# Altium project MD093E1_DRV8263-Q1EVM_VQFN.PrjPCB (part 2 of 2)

## Sheet MD093E1_DRV8263-Q1EVM_VQFN.SchDoc
size 431 x 279 mm; Date: Not shown in title block; ApprovedBy: Not shown in title block; CheckedBy: Not shown in title block; Author: Not shown in title block; CompanyName: Not shown in title block; Engineer: Not shown in title block; Organization: Not shown in title block; Address1: Not shown in title block; Address2: Not shown in title block; Address3: Not shown in title block; Address4: Not shown in title block; DocumentNumber: 2; Revision: Use project parameter SCH_Rev; SheetNumber: 2; SheetTotal: 3; PageSetup: Record=PageOptions¦CenterHorizontal=True¦CenterVertical=True¦PrintScale=1.00¦XCorrection=1.00¦YCorrection=1.00¦PrintKind=0¦BorderSize=5000000¦LeftOffset=0¦BottomOffset=0¦Orientation=2¦PaperLength=1000¦PaperWidth=1000¦Scale=100¦PaperSource=15¦PrintQuality=600¦MediaType=1¦DitherType=10¦PaperKind=Letter¦PrintScaleMode=1

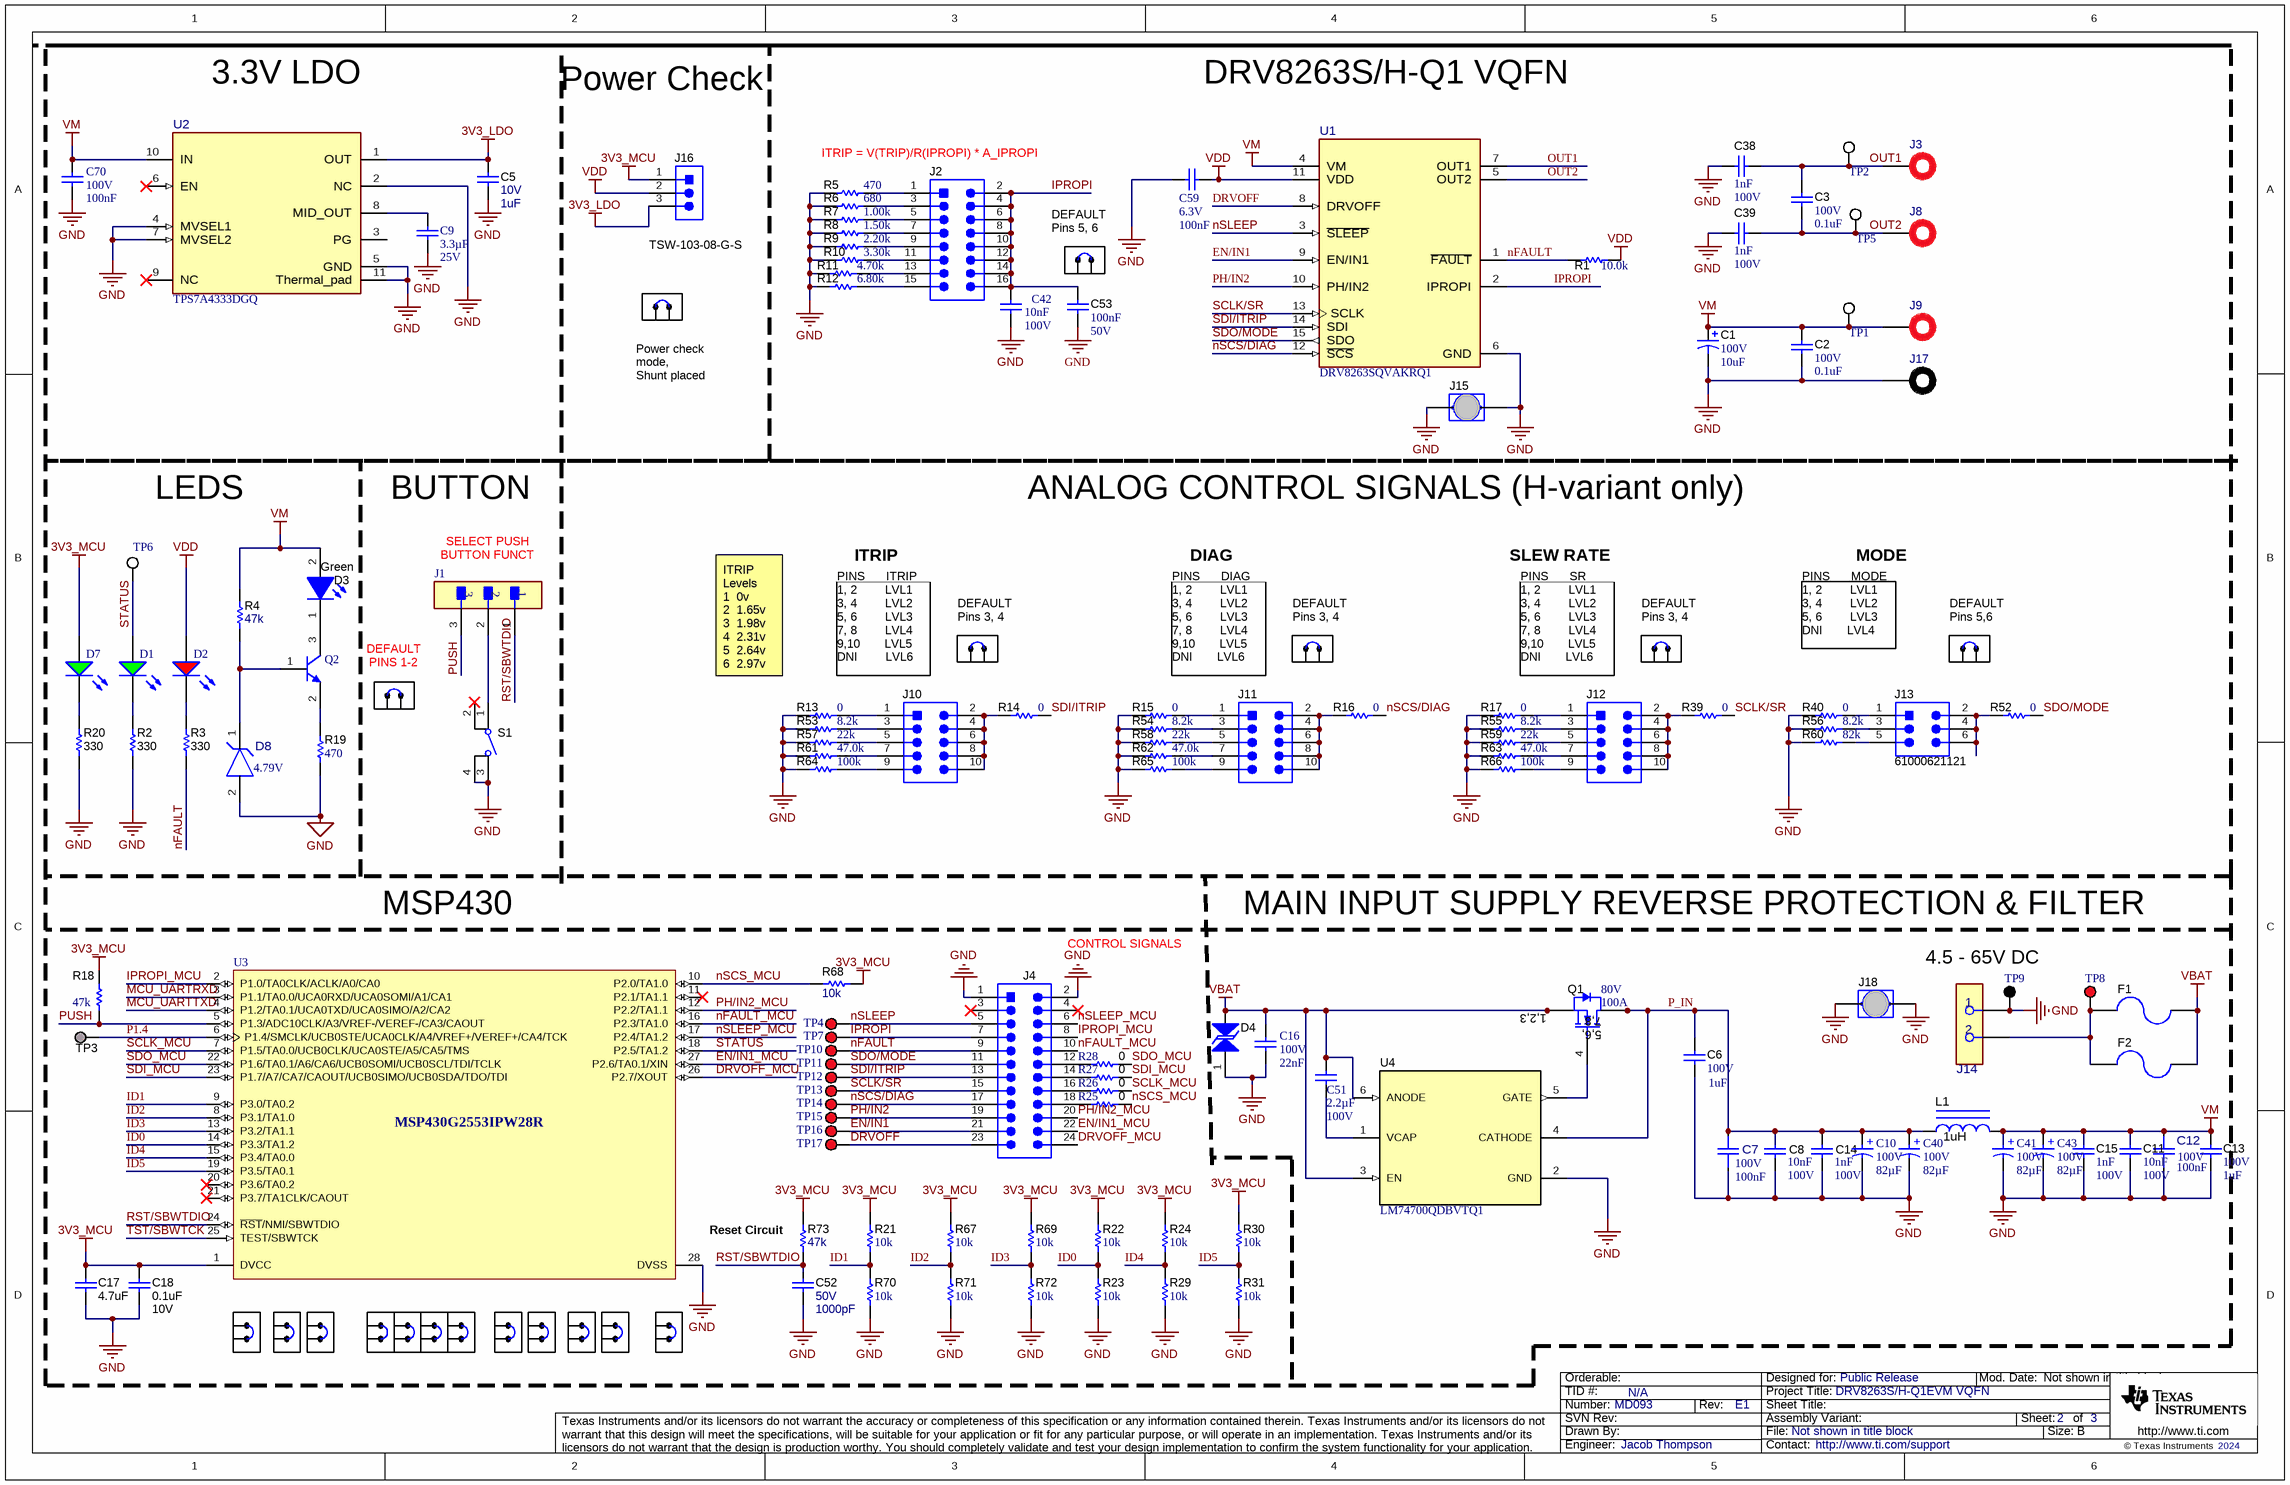
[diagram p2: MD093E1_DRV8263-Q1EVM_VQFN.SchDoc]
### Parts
C1  VDC_V: 100V  ValueDisplayed: 10uF  [SM_RADIAL_E]  (hidden comment: EEE-2AA100UP)
C2  VDC_V: 100V  ValueDisplayed: 0.1uF  [1206_180]  (hidden comment: C3216X7R2A104K160AA)
C3  VDC_V: 100V  ValueDisplayed: 0.1uF  [1206_180]  (hidden comment: C3216X7R2A104K160AA)
C5  VDC_V: 10V  ValueDisplayed: 1uF  [0402]  (hidden comment: 885012105012)
C6  VDC_V: 100V  ValueDisplayed: 1uF  [0805_HV]  (hidden comment: C2012X7S2A105K125AB)
C7  VDC_V: 100V  Cap_F: 100nF  [FP-885012206120_0603-MFG]  (hidden comment: 885012206120)
C8  Cap_F: 10nF  VDC_V: 100V  [0603]  (hidden comment: 885012206114)
C9  Cap_F: 3.3µF  Rated Voltage (DC): 25V  [WCAP-CSGP_1210_L3.2W2.5H1.6]  (hidden comment: 885012209026)
C10  Cap_F: 82µF  Rated Voltage (DC): 100V  [WCAP-ATUL_D10H20]  (hidden comment: 860040875004)
C11  Cap_F: 10nF  VDC_V: 100V  [0603]  (hidden comment: 885012206114)
C12  VDC_V: 100V  Cap_F: 100nF  [FP-885012206120_0603-MFG]  (hidden comment: 885012206120)
C13  VDC_V: 100V  ValueDisplayed: 1uF  [0805_HV]  (hidden comment: C2012X7S2A105K125AB)
C14  Cap_F: 1nF  VDC_V: 100V  [0603]  (hidden comment: 06031C102KAT2A)
C15  Cap_F: 1nF  VDC_V: 100V  [0603]  (hidden comment: 06031C102KAT2A)
C16  Cap_F: 22nF  Rated Voltage (DC): 100V  [WCAP-CSGP_0805_L2W1.25H0.8_Reflow]  (hidden comment: 885012207124)
C17  ValueDisplayed: 4.7uF  [0402_065L]  (hidden comment: Capacitor)
C18  ValueDisplayed: 0.1uF  VDC_V: 10V  [0603L]  (hidden comment: 885012206020)
C38  Cap_F: 1nF  VDC_V: 100V  [0603]  (hidden comment: CGA3E2X7R2A102K080AA)
C39  Cap_F: 1nF  VDC_V: 100V  [0603]  (hidden comment: CGA3E2X7R2A102K080AA)
C40  Cap_F: 82µF  Rated Voltage (DC): 100V  [WCAP-ATUL_D10H20]  (hidden comment: 860040875004)
C41  Cap_F: 82µF  Rated Voltage (DC): 100V  [WCAP-ATUL_D10H20]  (hidden comment: 860040875004)
C42  Cap_F: 10nF  Rated Voltage (DC): 100V  [WCAP-CSST_0805_L2W1.25H1.25]  (hidden comment: 885382207009)
C43  Cap_F: 82µF  Rated Voltage (DC): 100V  [WCAP-ATUL_D10H20]  (hidden comment: 860040875004)
C51  Cap_F: 2.2µF  Rated Voltage (DC): 100V  [WCAP-CSST_1210_L3.2W2.5H2.5]  (hidden comment: 885382209002)
C52  VDC_V: 50V  ValueDisplayed: 1000pF  [0402]  (hidden comment: GRM155R71H102KA01D)
C53  Cap_F: 100nF  VDC_V: 50V  [0603]  (hidden comment: CGA3E2X7R1H104K080AA)
C59  Cap_F: 100nF  Rated Voltage (DC): 6.3V  [WCAP-CSGP_0402_L1W0.5H0.5]  (hidden comment: 885012105001)
C70  Cap_F: 100nF  Rated Voltage (DC): 100V  [WCAP-CSGP_0805_L2W1.25H1.25]  (hidden comment: 885012207128)
D1  150080VS75000  [WL-SMCW_0805_150080xx75000]  (value not drawn)
D2  150080SS75000  [WL-SMCW_0805_150080xx75000]  (value not drawn)
D3  value Green  [WL-SMCW_GREEN]  (hidden comment: 150060VS75000)
D4  SMBJ33CA-13-F  [SMB-Bi]  (value not drawn)
D7  150080VS75000  [WL-SMCW_0805_150080xx75000]  (value not drawn)
D8  Vf_V: 4.79V  [FP-BZX84J-B4V7,115_SC90-MFG]  (hidden comment: BZX84J-B4V7,115)
F1  0463030.ER  [Fuse_0463]  (value not drawn)
F2  0463030.ER  [Fuse_0463]  (value not drawn)
J1  PR20203VBNN  [FP-PR20203VBNN-MFG]  (value not drawn)
J2  TSM-108-01-L-DV  [Samtec_TSM-108-01-x-DV]  (value not drawn)
J3  CT3151SP-2  [CTE_CT3151SP-2]  (value not drawn)
J4  67997-224HLF  [FCI_67997-224HLF]  (value not drawn)
J8  CT3151SP-2  [CTE_CT3151SP-2]  (value not drawn)
J9  CT3151SP-2  [CTE_CT3151SP-2]  (value not drawn)
J10  TSM-105-01-L-DV-P  [Samtec_TSM-105-01-x-DV]  (value not drawn)
J11  TSM-105-01-L-DV-P  [Samtec_TSM-105-01-x-DV]  (value not drawn)
J12  TSM-105-01-L-DV-P  [Samtec_TSM-105-01-x-DV]  (value not drawn)
J13  61000621121  [Wurth_61000621121]
J14  691256610002  [FP-691256610002_HDR2-MFG]  (value not drawn)
J15  D3082-05  [Harwin_D3082-05]  (value not drawn)
J16  TSW-103-08-G-S  [Samtec_TSW-103-08-x-S]
J17  CT3151SP-0  [CTE_CT3151SP-0]  (value not drawn)
J18  D3082-05  [Harwin_D3082-05]  (value not drawn)
L1  ValueDisplayed: 1uH  [WE-HCC_1210]  (hidden comment: 7443320100)
Q1  VdsMax_V: 80V  IdsMax_A: 100A  [DNK0008A]  (hidden comment: CSD19502Q5B)
Q2  BC846BLT1G  [ONSC-SOT-23-3-318-08_V]  (value not drawn)
R1  ValueDisplayed: 10.0k  [0603]  (hidden comment: RNCF0603TKY10K0)
R2  ValueDisplayed: 330  [0603L]  (hidden comment: CMP-0025785-4)
R3  ValueDisplayed: 330  [0603L]  (hidden comment: CMP-0025785-4)
R4  ValueDisplayed: 47k  [0402]  (hidden comment: CRCW040247K0JNED)
R5  ValueDisplayed: 470  [0603]  (hidden comment: RC0603FR-07470RL)
R6  ValueDisplayed: 680  [0603]  (hidden comment: RC0603FR-07680RL)
R7  ValueDisplayed: 1.00k  [0603]  (hidden comment: RC0603FR-071KL)
R8  ValueDisplayed: 1.50k  [0603]  (hidden comment: RC0603FR-071K5L)
R9  ValueDisplayed: 2.20k  [0603]  (hidden comment: RC0603FR-072K2L)
R10  ValueDisplayed: 3.30k  [0603]  (hidden comment: RC0603FR-073K3L)
R11  ValueDisplayed: 4.70k  [0603]  (hidden comment: RC0603FR-074K7L)
R12  ValueDisplayed: 6.80k  [0603]  (hidden comment: RC0603FR-076K8L)
R13  ValueDisplayed: 0  [0603]  (hidden comment: PMR03EZPJ000)
R14  ValueDisplayed: 0  [0603]  (hidden comment: PMR03EZPJ000)
R15  ValueDisplayed: 0  [0603]  (hidden comment: PMR03EZPJ000)
R16  ValueDisplayed: 0  [0603]  (hidden comment: PMR03EZPJ000)
R17  ValueDisplayed: 0  [0603]  (hidden comment: PMR03EZPJ000)
R18  ValueDisplayed: 47k  [0603]  (hidden comment: RC0603JR-0747KL)
R19  ValueDisplayed: 470  [0603]  (hidden comment: RC0603FR-07470RL)
R20  ValueDisplayed: 330  [0603L]  (hidden comment: CMP-0025785-4)
R21  ValueDisplayed: 10k  [0603]  (hidden comment: RC0603JR-0710KL)
R22  ValueDisplayed: 10k  [0603]  (hidden comment: RC0603JR-0710KL)
R23  ValueDisplayed: 10k  [0603]  (hidden comment: RC0603JR-0710KL)
R24  ValueDisplayed: 10k  [0603]  (hidden comment: RC0603JR-0710KL)
R25  value 0  [RESC1609X55X30NL10T20]  (hidden comment: CRCW06030000Z0EAHP)
R26  value 0  [RESC1609X55X30NL10T20]  (hidden comment: CRCW06030000Z0EAHP)
R27  value 0  [RESC1609X55X30NL10T20]  (hidden comment: CRCW06030000Z0EAHP)
R28  value 0  [RESC1609X55X30NL10T20]  (hidden comment: CRCW06030000Z0EAHP)
R29  ValueDisplayed: 10k  [0603]  (hidden comment: RC0603JR-0710KL)
R30  ValueDisplayed: 10k  [0603]  (hidden comment: RC0603JR-0710KL)
R31  ValueDisplayed: 10k  [0603]  (hidden comment: RC0603JR-0710KL)
R39  ValueDisplayed: 0  [0603]  (hidden comment: PMR03EZPJ000)
R40  ValueDisplayed: 0  [0603]  (hidden comment: PMR03EZPJ000)
R52  ValueDisplayed: 0  [0603]  (hidden comment: PMR03EZPJ000)
R53  ValueDisplayed: 8.2k  [0603]  (hidden comment: CRCW06038K20JNEA)
R54  ValueDisplayed: 8.2k  [0603]  (hidden comment: CRCW06038K20JNEA)
R55  ValueDisplayed: 8.2k  [0603]  (hidden comment: CRCW06038K20JNEA)
R56  ValueDisplayed: 8.2k  [0603]  (hidden comment: CRCW06038K20JNEA)
R57  ValueDisplayed: 22k  [0603]  (hidden comment: CRCW060322K0JNEA)
R58  ValueDisplayed: 22k  [0603]  (hidden comment: CRCW060322K0JNEA)
R59  ValueDisplayed: 22k  [0603]  (hidden comment: CRCW060322K0JNEA)
R60  ValueDisplayed: 82k  [0603]  (hidden comment: CRCW060382K0JNEA)
R61  ValueDisplayed: 47.0k  [0603]  (hidden comment: CRCW060347K0FKEA)
R62  ValueDisplayed: 47.0k  [0603]  (hidden comment: CRCW060347K0FKEA)
R63  ValueDisplayed: 47.0k  [0603]  (hidden comment: CRCW060347K0FKEA)
R64  ValueDisplayed: 100k  [0603]  (hidden comment: CRCW0603100KDHEAP)
R65  ValueDisplayed: 100k  [0603]  (hidden comment: CRCW0603100KDHEAP)
R66  ValueDisplayed: 100k  [0603]  (hidden comment: CRCW0603100KDHEAP)
R67  ValueDisplayed: 10k  [0603]  (hidden comment: RC0603JR-0710KL)
R68  ValueDisplayed: 10k  [0603]  (hidden comment: RC0603JR-0710KL)
R69  ValueDisplayed: 10k  [0603]  (hidden comment: RC0603JR-0710KL)
R70  ValueDisplayed: 10k  [0603]  (hidden comment: RC0603JR-0710KL)
R71  ValueDisplayed: 10k  [0603]  (hidden comment: RC0603JR-0710KL)
R72  ValueDisplayed: 10k  [0603]  (hidden comment: RC0603JR-0710KL)
R73  ValueDisplayed: 47k  [0402]  (hidden comment: CRCW040247K0JNED)
S1  FSM4JSMA  [SW_FSM4JSMA]  (value not drawn)
SH-J1  60900213421  [Wurth_60900213421]  (value not drawn)
SH-J2  60900213421  [Wurth_60900213421]  (value not drawn)
SH-J3  60900213421  [Wurth_60900213421]  (value not drawn)
SH-J4  60900213421  [Wurth_60900213421]  (value not drawn)
SH-J5  60900213421  [Wurth_60900213421]  (value not drawn)
SH-J6  60900213421  [Wurth_60900213421]  (value not drawn)
SH-J7  60900213421  [Wurth_60900213421]  (value not drawn)
SH-J8  60900213421  [Wurth_60900213421]  (value not drawn)
SH-J13  60900213421  [Wurth_60900213421]  (value not drawn)
SH-J14  60900213421  [Wurth_60900213421]  (value not drawn)
SH-J15  60900213421  [Wurth_60900213421]  (value not drawn)
SH-J16  60900213421  [Wurth_60900213421]  (value not drawn)
SH-J18  60900213421  [Wurth_60900213421]  (value not drawn)
SH-J19  60900213421  [Wurth_60900213421]  (value not drawn)
SH-J20  60900213421  [Wurth_60900213421]  (value not drawn)
SH-J21  60900213421  [Wurth_60900213421]  (value not drawn)
SH-J22  60900213421  [Wurth_60900213421]  (value not drawn)
SH-J23  60900213421  [Wurth_60900213421]  (value not drawn)
SH-J24  60900213421  [Wurth_60900213421]  (value not drawn)
TP1  5016  [Testpoint_Keystone_Compact]  (value not drawn)
TP2  5016  [Testpoint_Keystone_Compact]  (value not drawn)
TP3  TP_H0.45P0.75  [TP_H045P075]  (value not drawn)  (no BOM)
TP4  5010  [Keystone5010]  (value not drawn)
TP5  5016  [Testpoint_Keystone_Compact]  (value not drawn)
TP6  5015  [Testpoint_Keystone_Miniature]  (value not drawn)
TP7  5010  [Keystone5010]  (value not drawn)
TP8  5010  [Keystone5010]  (value not drawn)
TP9  5011  [Keystone5011]  (value not drawn)
TP10  5010  [Keystone5010]  (value not drawn)
TP11  5010  [Keystone5010]  (value not drawn)
TP12  5010  [Keystone5010]  (value not drawn)
TP13  5010  [Keystone5010]  (value not drawn)
TP14  5010  [Keystone5010]  (value not drawn)
TP15  5010  [Keystone5010]  (value not drawn)
TP16  5010  [Keystone5010]  (value not drawn)
TP17  5010  [Keystone5010]  (value not drawn)
U1  DRV8263SQVAKRQ1  [VAK0015A-MFG]
U2  TPS7A4333DGQ  [DGQ0010E-MFG]
U3  MSP430G2553IPW28R  [PW0028A_N]
U4  LM74700QDBVTQ1  [DBV0006A_N]

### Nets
3V3_LDO: C5.1 J16.3 U2.1(OUT)
3V3_MCU: C17.1 C18.1 D7.2(A) J16.1 R18.2 R21.1 R22.1 R24.1 R30.1 R67.1 R68.1 R69.1 R73.2 U3.1(DVCC)
GND: C1.2(-) C2.2 C5.2 C6.1 C7.1 C8.1 C9.2 C10.2(N) C11.1 C12.1 C13.1 C14.2 C15.2 C16.2 C17.2 C18.2 C38.1 C39.1 C40.2(N) C41.2(N) C42.1 C43.2(N) C52.2 C53.2 C59.2 C70.2 D4.1 D8.2(anode) J4.1 J4.2 J14.1 J15.1 J15.2 J17.1 J18.1 J18.2 R2.1 R5.1 R6.1 R7.1 R8.1 R9.1 R10.1 R11.1 R12.1 R13.2 R15.2 R17.2 R19.1 R20.1 R23.2 R29.2 R31.2 R40.2 R53.1 R54.1 R55.1 R56.1 R57.1 R58.1 R59.1 R60.2 R61.1 R62.1 R63.1 R64.1 R65.1 R66.1 R70.2 R71.2 R72.2 S1.3 S1.4 TP9.1 U1.6(GND) U2.2(NC) U2.4(MVSEL1) U2.5(GND) U2.7(MVSEL2) U2.11(Thermal_pad) U3.28(DVSS) U4.2(GND)
VBAT: C16.1 C51.2 D4.2 F1.1 F2.1 Q1.1(S) Q1.2(S) Q1.3(S) U4.3(EN) U4.6(ANODE)
VDD: C59.1 D2.2(A) J16.2 R1.2 U1.11(VDD)
VM: C1.1(+) C2.1 C11.2 C12.2 C13.2 C15.1 C41.1(P) C43.1(P) C70.1 D3.2(A) J9.1 L1.2 R4.2 TP1.1 U1.4(VM) U2.10(IN)
DRVOFF: J4.23 TP17.1 U1.8(DRVOFF)
DRVOFF_MCU: J4.24 U3.26(P2.7/XOUT)
EN/IN1: J4.21 TP16.1 U1.9(EN/IN1)
EN/IN1_MCU: J4.22 U3.27(P2.6/TA0.1/XIN)
ID0: R22.2 R23.1 U3.14(P3.3/TA1.2)
ID1: R21.2 R70.1 U3.9(P3.0/TA0.2)
ID2: R67.2 R71.1 U3.8(P3.1/TA1.0)
ID3: R69.2 R72.1 U3.13(P3.2/TA1.1)
ID4: R24.2 R29.1 U3.15(P3.4/TA0.0)
ID5: R30.2 R31.1 U3.19(P3.5/TA0.1)
IPROPI: C42.2 C53.1 J2.2 J2.4 J2.6 J2.8 J2.10 J2.12 J2.14 J2.16 J4.7 TP7.1 U1.2(IPROPI)
IPROPI_MCU: J4.8 U3.2(P1.0/TA0CLK/ACLK/A0/CA0)
MCU_UARTRXD: U3.3(P1.1/TA0.0/UCA0RXD/UCA0SOMI/A1/CA1)
MCU_UARTTXD: U3.4(P1.2/TA0.1/UCA0TXD/UCA0SIMO/A2/CA2)
nFAULT: J4.9 R1.1 R3.1 TP10.1 U1.1(~{FAULT})
nFAULT_MCU: J4.10 U3.16(P2.3/TA1.0)
nSCS/DIAG: J4.17 R16.1 TP14.1 U1.12(~{SCS})
nSCS_MCU: R25.2 R68.2 U3.10(P2.0/TA1.0)
nSLEEP: J4.5 TP4.1 U1.3(~{SLEEP})
nSLEEP_MCU: J4.6 U3.17(P2.4/TA1.2)
OUT1: C3.1 C38.2 J3.1 TP2.1 U1.7(OUT1)
OUT2: C3.2 C39.2 J8.1 TP5.1 U1.5(OUT2)
P1.4: TP3.1 U3.6(P1.4/SMCLK/UCB0STE/UCA0CLK/A4/VREF+/VEREF+/CA4/TCK)
P_IN: C6.2 C7.2 C8.2 C10.1(P) C14.1 C40.1(P) L1.1 Q1.5(D) Q1.6(D) Q1.7(D) Q1.8(D) Q1.9(D) U4.4(CATHODE)
PH/IN2: J4.19 TP15.1 U1.10(PH/IN2)
PH/IN2_MCU: J4.20 U3.12(P2.2/TA1.1)
PUSH: J1.3 R18.1 U3.5(P1.3/ADC10CLK/A3/VREF-/VEREF-/CA3/CAOUT)
RST/SBWTDIO: C52.1 J1.1 R73.1 U3.24(~{RST}/NMI/SBWTDIO)
SCLK/SR: J4.15 R39.1 TP13.1 U1.13(SCLK)
SCLK_MCU: R26.2 U3.7(P1.5/TA0.0/UCB0CLK/UCA0STE/A5/CA5/TMS)
SDI/ITRIP: J4.13 R14.1 TP12.1 U1.14(SDI)
SDI_MCU: R27.2 U3.23(P1.7/A7/CA7/CAOUT/UCB0SIMO/UCB0SDA/TDO/TDI)
SDO/MODE: J4.11 R52.1 TP11.1 U1.15(SDO)
SDO_MCU: R28.2 U3.22(P1.6/TA0.1/A6/CA6/UCB0SOMI/UCB0SCL/TDI/TCLK)
STATUS: D1.2(A) TP6.1 U3.18(P2.5/TA1.2)
TST/SBWTCK: U3.25(TEST/SBWTCK)
NetC9_1: C9.1 U2.8(MID_OUT)
NetC51_1: C51.1 U4.1(VCAP)
NetD1_1: D1.1(K) R2.2
NetD2_1: D2.1(K) R3.2
NetD3_1: D3.1(K) Q2.3(C)
NetD7_1: D7.1(K) R20.2
NetD8_1: D8.1(cathode) Q2.1(B) R4.1
NetF1_2: F1.2 F2.2 J14.2 TP8.1
NetJ1_2: J1.2 S1.1
NetJ2_1: J2.1 R5.2
NetJ2_3: J2.3 R6.2
NetJ2_5: J2.5 R7.2
NetJ2_7: J2.7 R8.2
NetJ2_9: J2.9 R9.2
NetJ2_11: J2.11 R10.2
NetJ2_13: J2.13 R11.2
NetJ2_15: J2.15 R12.2
NetJ4_12: J4.12 R28.1
NetJ4_14: J4.14 R27.1
NetJ4_16: J4.16 R26.1
NetJ4_18: J4.18 R25.1
NetJ10_1: J10.1 R13.1
NetJ10_2: J10.2 J10.4 J10.6 J10.8 J10.10 R14.2
NetJ10_3: J10.3 R53.2
NetJ10_5: J10.5 R57.2
NetJ10_7: J10.7 R61.2
NetJ10_9: J10.9 R64.2
NetJ11_1: J11.1 R15.1
NetJ11_2: J11.2 J11.4 J11.6 J11.8 J11.10 R16.2
NetJ11_3: J11.3 R54.2
NetJ11_5: J11.5 R58.2
NetJ11_7: J11.7 R62.2
NetJ11_9: J11.9 R65.2
NetJ12_1: J12.1 R17.1
NetJ12_2: J12.2 J12.4 J12.6 J12.8 J12.10 R39.2
NetJ12_3: J12.3 R55.2
NetJ12_5: J12.5 R59.2
NetJ12_7: J12.7 R63.2
NetJ12_9: J12.9 R66.2
NetJ13_1: J13.1 R40.1
NetJ13_2: J13.2 J13.4 J13.6 R52.2
NetJ13_3: J13.3 R56.2
NetJ13_5: J13.5 R60.1
NetQ1_4: Q1.4(G) U4.5(GATE)
NetQ2_2: Q2.2(E) R19.2

Not connected (* = marked no-connect by the designer): J4 3* 4*; S1 2*; U2 3(PG) 6(EN)* 9(NC)*; U3 11(P2.1/TA1.1)* 20(P3.6/TA0.2)* 21(P3.7/TA1CLK/CAOUT)*

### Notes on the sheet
- 3.3V LDO
- Power Check
- DRV8263S/H-Q1 VQFN
- ITRIP = V(TRIP)/R(IPROPI) * A_IPROPI
- (near SH-J6) DEFAULT
  Pins 5, 6
- (near SH-J20) Power check mode,
  Shunt placed
- LEDS
- BUTTON
- ANALOG CONTROL SIGNALS (H-variant only)
- SELECT PUSH
- (near J1) BUTTON FUNCT
- ITRIP
- DIAG
- SLEW RATE
- MODE
- PINS      ITRIP
- (near SH-J3) DEFAULT
  Pins 3, 4
- PINS      DIAG
- (near SH-J4) DEFAULT
  Pins 3, 4
- PINS      SR
- (near SH-J5) DEFAULT
  Pins 3, 4
- PINS      MODE
- (near SH-J2) DEFAULT
  Pins 5,6
- DEFAULT
- (near SH-J1) PINS 1-2
- ITRIP Levels
  1  0v
  2  1.65v
  3  1.98v
  4  2.31v
  5  2.64v
  6  2.97v
- 1, 2        LVL1
  3, 4        LVL2
  5, 6        LVL3
  7, 8        LVL4
  9,10       LVL5
  DNI        LVL6
- 1, 2        LVL1
  3, 4        LVL2
  5, 6        LVL3
  7, 8        LVL4
  9,10       LVL5
  DNI       LVL6
- 1, 2        LVL1
  3, 4        LVL2
  5, 6        LVL3
  DNI       LVL4
- MSP430
- MAIN INPUT SUPPLY REVERSE PROTECTION & FILTER
- CONTROL SIGNALS
- 4.5 - 65V DC
- (near R73) Reset Circuit

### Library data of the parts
C1 = CMP-0011164-2: CAP, AL, 10 uF, 100 V, +/- 20%, AEC-Q200 Grade 3, SMD; Manufacturer: Panasonic; TaMin_C: -40°C; Polarized: Y; SizeAreaWB_mm2: 118.45; Value1: Unknown; U/M: EA; Value: 10uF; TaMax_C: 85°C; SizeZ_mm: 6.2; SizeX_mm: 9.5; SizeY_mm: 8.3; Cap_Case: 8.0x6.0mm; SizeArea_mm2: 78.85; CompType: Capacitor; Cap_F: 10µF; IRMS_A: 50mA; AEC Grade: 3; AEC Category: Q200
C2 C3 = CMP-0008709-2: CAP, CERM, 0.1 uF, 100 V, +/- 10%, X7R, 1206; Manufacturer: TDK; TaMin_C: -55°C; ESR_ohm: 30.343m; Polarized: N; SizeAreaWB_mm2: 10.92; Value1: 0.030343 ohm; U/M: EA; Value: 0.1uF; TaMax_C: 125°C; SizeZ_mm: 1.8; SizeX_mm: 3.2; SizeY_mm: 1.6; SizeArea_mm2: 5.12; Cap_F: 100nF; IRMS_A: 1.338A; AEC Category: Q200
C5 = CMP-0064924-2: CAP, CERM, 1 uF, 10 V,+/- 20%, X5R, 0402; Manufacturer: Wurth Elektronik; TaMin_C: -55°C; Polarized: N; SizeAreaWB_mm2: 3; Value1: Unknown; U/M: EA; Value: 1uF; TaMax_C: 85°C; SizeZ_mm: 0.6; SizeX_mm: 1; SizeY_mm: 0.5; Cap_F: 1µF; AEC Category: Q200
C6 C13 = CMP-0007891-2: CAP, CERM, 1 uF, 100 V, +/- 10%, X7S, 0805; Manufacturer: TDK; TaMin_C: -55°C; ESR_ohm: 8.255m; Polarized: N; SizeAreaWB_mm2: 6.75; Value1: 0.008255 ohm; U/M: EA; Value: 1uF; TaMax_C: 125°C; SizeZ_mm: 1.45; SizeX_mm: 2; SizeY_mm: 1.25; Cap_Case: 0805; SizeArea_mm2: 2.5; Cap_F: 1µF; IRMS_A: 2.27442A; AEC Category: Q200
C7 C12 = CMP-0097294-1: 0.1 µF ±10% 100V Ceramic Capacitor X7R 0603 (1608 Metric); Manufacturer: Wurth Electronics; TempCo: 15%; SizeZ_mm: 0.87mm; Value: 100nF; AEC Qualified: No
C8 C11 = CMP-0079993-1: CAP, CERM, 0.01 µF, 100 V,+/- 10%, X7R, 0603; Manufacturer: Wurth Elektronik; TaMin_C: -55°C; Polarized: N; SizeAreaWB_mm2: 4.68; U/M: EA; Value: 0.01uF; TaMax_C: 105°C; SizeZ_mm: 1; SizeX_mm: 1.6; SizeY_mm: 0.8; SizeArea_mm2: 1.28; AEC Category: Q200; ValueDisplayed: 0.01µF
C9 = CMP-0105009-1: WCAP-CSGP Multilayer Ceramic Chip Capacitor, General Purpose, size 1210, X7R, 3.3µF, 25VDC; Manufacturer: Wurth Elektronik; Capacitance Tolerance: +/-10%; Dissipation Factor: 3.5%; Insulation Resistance: 0.2GOhm; Technical Reference: X7R1210335K025DFCT10000
C10 C40 C41 C43 = CMP-0102582-1: WCAP-ATUL Aluminum Electrolytic Capacitor, Radial, THT, D10 x H20mm, 82µF, 100V; Manufacturer: Wurth Elektronik; Capacitance Tolerance: 20%; Dissipation Factor: 9%; Endurance: 7000h; Leakage Current: 82uA; Ripple Current: 600mA; Technical Reference: ATDF200820M100DSPAAG000
C14 C15 = CMP-0006724-5: CAP, CERM, 1000 pF, 100 V, +/- 10%, X7R, 0603; Manufacturer: AVX; TaMin_C: -55°C; ESR_ohm: 2.76d; Polarized: N; SizeAreaWB_mm2: 4.68; Value1: 0.276 ohm; U/M: EA; Value: 1000pF; TaMax_C: 125°C; SizeZ_mm: 1; SizeX_mm: 1.6; SizeY_mm: 0.8; SizeArea_mm2: 1.28; AEC Category: Q200
C16 = CMP-0115610-1: WCAP-CSGP Multilayer Ceramic Chip Capacitor, General Purpose, size 0805, X7R, 22nF, 100VDC; Manufacturer: Wurth Elektronik; Capacitance Tolerance: +/-10%; Dissipation Factor: 2.5%; Insulation Resistance: 4.5GOhm; Technical Reference: X7R0805223K100DFCT10000
C17 = CMP-0006268-2: CAP, CERM, 4.7 uF, 10 V, +/- 10%, X5R, 0402; PartNumber: C1005X5R1A475K050BC; Manufacturer: TDK; Polarized: N; Value: 4.7uF; U/M: EA; Cap_F: 4.7µF; ESR_ohm: 3.417m; Value1: 0.003417 ohm; VDC_V: 10V; IRMS_A: 2.7063A; TaMin_C: -55°C; TaMax_C: 85°C; Cap_Case: 0402_065; AEC Category: Q200; SizeArea_mm2: 0.5; SizeAreaWB_mm2: 3; SizeX_mm: 1; SizeZ_mm: 0.65
C18 = CMP-0064931-4: CAP, CERM, 0.1 uF, 10 V,+/- 10%, X7R, 0603; Manufacturer: Wurth Elektronik; Polarized: N; CompType: Capacitor; Value: 0.1uF; U/M: EA; Cap_F: 100nF; Value1: Unknown; TaMin_C: -55°C; TaMax_C: 125°C; Cap_Case: 0603; AEC Category: Q200; SizeArea_mm2: 1.28; SizeAreaWB_mm2: 4.68; SizeX_mm: 1.6; SizeY_mm: 0.8; SizeZ_mm: 1
C38 C39 = CMP-0007081-4: CAP, CERM, 1000 pF, 100 V, +/- 10%, X7R, AEC-Q200 Grade 1, 0603; Manufacturer: TDK; TaMin_C: -55°C; ESR_ohm: 1.97137; Polarized: N; SizeAreaWB_mm2: 4.68; Value1: 1.97137 ohm; U/M: EA; Value: 1000pF; TaMax_C: 125°C; SizeZ_mm: 1; SizeX_mm: 1.6; SizeY_mm: 0.8; SizeArea_mm2: 1.28; AEC Qualified: Y; IRMS_A: 305.705mA; AEC Category: Q200
C42 = CMP-0105213-1: WCAP-CSST Multilayer Ceramic Chip Capacitor, Soft Termination, size 0805, X7R Class II, 10nF, 100VDC; Manufacturer: Wurth Elektronik; Capacitance Tolerance: +/-10%; Dissipation Factor: 2.5%; Insulation Resistance: 10GOhm; Technical Reference: X7R0805103K100DFCT1S000
C51 = CMP-0119921-1: WCAP-CSST Multilayer Ceramic Chip Capacitor, Soft Termination, size 1210, X7R Class II, 2.2µF, 100VDC; Manufacturer: Wurth Elektronik; Capacitance Tolerance: +/-10%; Dissipation Factor: 5%; Insulation Resistance: 0.05GOhm; Technical Reference: X7R1210225K100DFCT1S000
C52 = CMP-0006673-2: CAP, CERM, 1000 pF, 50 V, +/- 10%, X7R, 0402; Manufacturer: MuRata; TaMin_C: -55°C; Polarized: N; SizeAreaWB_mm2: 3; Value1: Unknown; U/M: EA; Value: 1000pF; TaMax_C: 125°C; SizeZ_mm: 0.6; SizeX_mm: 1; SizeY_mm: 0.5; Cap_F: 1nF; AEC Category: Q200
C53 = CMP-0007078-4: CAP, CERM, 0.1 uF, 50 V, +/- 10%, X7R, AEC-Q200 Grade 1, 0603; Manufacturer: TDK; TaMin_C: -55°C; ESR_ohm: 29.6m; Polarized: N; SizeAreaWB_mm2: 4.68; Value1: 0.0296 ohm; U/M: EA; Value: 0.1uF; TaMax_C: 125°C; SizeZ_mm: 1; SizeX_mm: 1.6; SizeY_mm: 0.8; SizeArea_mm2: 1.28; AEC Qualified: Y; IRMS_A: 971.99mA; AEC Category: Q200
C59 = CMP-0115207-1: WCAP-CSGP Multilayer Ceramic Chip Capacitor, General Purpose, size 0402, X5R, 100nF, 6.3VDC; Manufacturer: Wurth Elektronik; Capacitance Tolerance: +/-20%; Dissipation Factor: 10%; Insulation Resistance: 1GOhm; Technical Reference: X5R0402104M6R3DFCT10000
C70 = CMP-0108445-1: WCAP-CSGP Multilayer Ceramic Chip Capacitor, General Purpose, size 0805, X7R, 100nF, 100VDC; Manufacturer: Wurth Elektronik; Capacitance Tolerance: +/-10%; Dissipation Factor: 2.5%; Insulation Resistance: 1GOhm; Technical Reference: X7R0805104K100DFCT10000
D1 D7 = CMP-1426-00009-5: SMD mono-color Chip LED, WL-SMCW, Bright Green; NexarPartId: 29717783; Manufacturer: Wurth Elektronik; Dominant Wavelength: 570nm; Lens Style: Clear, Rectangular; Test Current: 20mA; Max Junction Temperature (Tj): 95°C; Max Reverse Voltage (DC): 5V; Forward Voltage: 2V; Forward Current: 100mA; Viewing Angle: 140°; Power Dissipation: 72mW; Peak Wavelength: 572nm; Luminous Intensity: 40mcd
D2 = CMP-1426-00010-3: SMD mono-color Chip LED, WL-SMCW, Super Red; NexarPartId: 29717782; Manufacturer: Wurth Elektronik; Peak Wavelength: 645nm; Luminous Intensity: 60mcd; Max Junction Temperature (Tj): 95°C; Wavelength: 630nm; Forward Current: 100mA; Max Reverse Voltage (DC): 5V; Lens Style: Clear, Rectangular; Test Current: 20mA; Power Dissipation: 72mW; Viewing Angle: 140°; Forward Voltage: 1.9V
D3 = CMP-0002894-2: LED, Green, SMD; Manufacturer: Wurth Elektronik; Type: AlInGaP; Value2: 2V; Io_A: 20mA; Value1: W
D4 = CMP-0005564-3: Diode, TVS, Bi, 33 V, SMB; Manufacturer: Diodes Inc.; Value: 33V; SizeX_mm: 5.6; Ppk: 600W; SizeAreaWB_mm2: 44.156; SizeZ_mm: 2.6; SizeArea_mm2: 21.336; SizeY_mm: 3.81; AEC Category: Q101
D8 = CMP-0097377-1: Diode Zener Single 4.7V 2% 550mW Automotive 2-Pin SOD-323F T/R; Manufacturer: Nexperia; TaMin_C: -55°C; Vr_V: 2V; SizeZ_mm: 0.8mm; Max Reverse Leakage Current: 3uA; TJmax_C: 150°C; Zener Impedance: 80Ω; AEC Grade: Grade 0; Forward Current: 250mA; TaMax_C: +150°C; AEC Qualified: Yes
F1 F2 = CMP-0077200-3: Fuse, 30 A, 250 VAC, 100 VDC, SMD; Manufacturer: Littelfuse; VAC_V: 250V; SizeAreaWB_mm2: 61.952; Rtyp_Ohm: 1.93m; SizeArea_mm2: 31.512; MeltingTyp: 916; Irating_A: 30A; SizeZ_mm: 3.12; VDC_V: 100V; SizeX_mm: 10.1; Interrupt_AC: 100A; Interrupt_DC: 50A; Fuse Speed: Fast; Fuse Technology: Board Mount; TaMax_C: 125°C; TaMin_C: -55°C
J1 = CMP-77940-000002-1: CONN HEADER VERT 3POS 2.54MM; Manufacturer: Metz Connect; Conn Orientation: Straight; Current Rating: 3A; Number Of Contacts: 3; Conn Gender: Male
J2 = CMP-0075595-1: Header, 2.54mm, 8x2, Gold, SMT; Manufacturer: Samtec; Pitch_mm: 2.54; Gender: Male; Cert_CSA: Y; Current_A: 4.9A; Voltage_V: 475V; CT: False; Shrouded: N; Row_Count: 2; CNHeader: True
J3 J8 J9 = CMP-0055418-2: Banana Jack Insul Nylon Red, R/A, TH; Manufacturer: Cal Test Electronics; CNHeader: FALSE; Current_A: 25A; Gender: Female; Voltage_V: 1kV; Row_Count: 1; ContactFinish: Nickel; CT: TRUE; Cert_UL: Y
J4 = CMP-0085938-1: Header, 2.54mm, 12x2, Gold, TH; Manufacturer: FCI; Current_A: 5A; Shrouded: N; Gender: Male; Voltage_V: 1.5kV; Row_Count: 2; Pitch_mm: 2.54; Cert_UL: Y
J10-J12 = CMP-0055598-2: Header, 2.54mm, 5x2, Gold, SMT; Manufacturer: Samtec; Current_A: 5.4A; Green_Lifecycle: Active; Shrouded: N; Gender: Male; Cert_CSA: Y; Green_REACh: Passed; Voltage_V: 475V; Row_Count: 2; RowSpacing_mm: 2.54
J13 = CMP-0079534-2: Header, 2.54mm, 3x2, Gold, SMT; Manufacturer: Wurth Elektronik; Pitch_mm: 2.54; Gender: Male; Cert_UL: Y; Current_A: 3A; Voltage_V: 250V; Shrouded: N; Row_Count: 2
J14 = CMP-0086764-1: Manufacturer: Wurth; Current_A: 57A; Voltage_V: 750V; ContactFinish: Zinc; Row_Count: 1
J15 J18 = CMP-0075110-1: 1mm Uninsulated Shorting Plug, 10.16mm spacing, TH; Manufacturer: Harwin; CNHeader: False; Green_Lifecycle: Active; Green_REACh: Passed; CompType: Jumper Wire
J16 = CMP-0079327-1: Header, 2.54mm, 3x1, Gold, TH; Manufacturer: Samtec; Cert_UL: Y; Row_Count: 1; Pitch_mm: 2.54; Gender: Male; Shrouded: N
J17 = CMP-0055417-2: Banana Jack Insul Nylon Black, R/A, TH; Manufacturer: Cal Test Electronics; CNHeader: FALSE; Current_A: 25A; Gender: Female; Voltage_V: 1kV; Row_Count: 1; ContactFinish: Nickel; CT: TRUE; Cert_UL: Y
L1 = CMP-0063986-1: Inductor, Shielded Drum Core, Ferrite, 1 uH, 24 A, 0.0012 ohm, SMD; Manufacturer: Wurth Elektronik; Isat: 32A @ 30% inductance drop; Irms: 24A @ 50C rise; Green_Lifecycle: Active; SizeAreaWB_mm2: 188.94; DCR_ohm: 1.2m; Green_REACh: Passed; Value: 1uH; Imax_A: 24A; SizeZ_mm: 10; SizeX_mm: 12.1; SizeY_mm: 11.4; SizeArea_mm2: 137.94; Ind_H: 1µH; AEC Category: Q200
Q1 = CMP-0000915-2: MOSFET, N-CH, 80 V, 100 A, DNK0008A (VSON-CLIP-8); Alternate Manufacturer: None; Manufacturer: Texas Instruments; SizeZ_mm: 1; ChType: N; Value2: 48 nC; SizeX_mm: 6; SizeY_mm: 5; Vgs_V: 20V; Value: 80V; SizeArea_mm2: 30; AEC Category: Q101; SizeAreaWB_mm2: 56; U/M: EA; QgTyp_nC: 48
Q2 = CMP-1048-00779-1: General Purpose Transistor, NPN Silicon, 3-Pin SOT-23, Pb-Free, Tape and Reel; Manufacturer: On Semiconductor; fT Min (MHz): 100; IC Continuous (A): 0.1
R1 = CMP-0023626-3: RES, 10.0 k, 0.01%, 0.063 W, 0603; Manufacturer: Stackpole Electronics Inc; Power_W: 63mW; TempCo: 5 ppm/C; Value_Code: 10k0; U/M: EA; Value: 10.0k; Res_ohm: 10k; SizeX_mm: 1.6; SizeY_mm: 0.8; SizeZ_mm: 1; Value2: 0.063W; SizeArea_mm2: 1.28; VDC_V: 50V; AEC Category: Q200
R2 R3 R20 = CMP-0025785-4: RES, 330, 5%, 0.1 W, AEC-Q200 Grade 0, 0603; PartNumber: CRCW0603330RJNEA; Manufacturer: Vishay-Dale; CompType: Resistor; Value: 330; Value_Code: 330R; Power_W: 100mW; Value2: 0.1W; VDC_V: 75V; TempCo: 200 ppm/C; EIA_Code: E24; AEC Category: Q200; AEC Qualified: Y; AEC Grade: 0; SizeX_mm: 1.6; SizeY_mm: 0.8; SizeZ_mm: 1; SizeArea_mm2: 1.28
R4 R73 = CMP-0026935-3: RES, 47 k, 5%, 0.063 W, AEC-Q200 Grade 0, 0402; Manufacturer: Vishay-Dale; Power_W: 63mW; TempCo: 200 ppm/C; Value_Code: 47k0; Value: 47k; EIA_Code: E24; SizeX_mm: 1; SizeY_mm: 0.5; SizeZ_mm: 0.6; Value2: 0.063W; AEC Qualified: Y; VDC_V: 50V; AEC Category: Q200; AEC Grade: 0
R5 R19 = CMP-0023129-5: RES, 470, 1%, 0.1 W, 0603; Manufacturer: Yageo; Power_W: 100mW; TempCo: 100 ppm/C; Value_Code: 470R; Value: 470; SizeX_mm: 1.6; SizeY_mm: 0.8; SizeZ_mm: 1; Value2: 0.1W; SizeArea_mm2: 1.28; AEC Qualified: N; VDC_V: 75V; AEC Category: Q200; SizeAreaWB_mm2: 4.68
R6 = CMP-0023235-5: RES, 680, 1%, 0.1 W, 0603; Manufacturer: Yageo; Power_W: 100mW; TempCo: 100 ppm/C; Value_Code: 680R; Value: 680; SizeX_mm: 1.6; SizeY_mm: 0.8; SizeZ_mm: 1; Value2: 0.1W; SizeArea_mm2: 1.28; AEC Qualified: N; VDC_V: 75V; AEC Category: Q200; SizeAreaWB_mm2: 4.68
R7 = CMP-0022895-5: RES, 1.00 k, 1%, 0.1 W, 0603; Manufacturer: Yageo; Power_W: 100mW; TempCo: 100 ppm/C; Value_Code: 1k00; Value: 1.00k; EIA_Code: E96; Res_ohm: 1k; SizeX_mm: 1.6; SizeY_mm: 0.8; SizeZ_mm: 1; Value2: 0.1W; SizeArea_mm2: 1.28; AEC Qualified: N; VDC_V: 75V; AEC Category: Q200; SizeAreaWB_mm2: 4.68
R8 = CMP-0022883-5: RES, 1.50 k, 1%, 0.1 W, 0603; Manufacturer: Yageo; Power_W: 100mW; TempCo: 100 ppm/C; Value_Code: 1k50; Value: 1.50k; EIA_Code: E96; Res_ohm: 1.5k; SizeX_mm: 1.6; SizeY_mm: 0.8; SizeZ_mm: 1; Value2: 0.1W; SizeArea_mm2: 1.28; AEC Qualified: N; VDC_V: 75V; AEC Category: Q200; SizeAreaWB_mm2: 4.68
R9 = CMP-0022986-5: RES, 2.20 k, 1%, 0.1 W, 0603; Manufacturer: Yageo; Power_W: 100mW; TempCo: 100 ppm/C; Value_Code: 2k20; Value: 2.20k; Res_ohm: 2.2k; SizeX_mm: 1.6; SizeY_mm: 0.8; SizeZ_mm: 1; Value2: 0.1W; SizeArea_mm2: 1.28; AEC Qualified: N; VDC_V: 75V; AEC Category: Q200; SizeAreaWB_mm2: 4.68
R10 = CMP-0023081-5: RES, 3.30 k, 1%, 0.1 W, 0603; Manufacturer: Yageo; Power_W: 100mW; TempCo: 100 ppm/C; Value_Code: 3k30; Value: 3.30k; Res_ohm: 3.3k; SizeX_mm: 1.6; SizeY_mm: 0.8; SizeZ_mm: 1; Value2: 0.1W; SizeArea_mm2: 1.28; AEC Qualified: N; VDC_V: 75V; AEC Category: Q200; SizeAreaWB_mm2: 4.68
R11 = CMP-0023153-5: RES, 4.70 k, 1%, 0.1 W, 0603; Manufacturer: Yageo; Power_W: 100mW; TempCo: 100 ppm/C; Value_Code: 4k70; Value: 4.70k; Res_ohm: 4.7k; SizeX_mm: 1.6; SizeY_mm: 0.8; SizeZ_mm: 1; Value2: 0.1W; SizeArea_mm2: 1.28; AEC Qualified: N; VDC_V: 75V; AEC Category: Q200; SizeAreaWB_mm2: 4.68
R12 = CMP-0023253-5: RES, 6.80 k, 1%, 0.1 W, 0603; Manufacturer: Yageo; Power_W: 100mW; TempCo: 100 ppm/C; Value_Code: 6k80; Value: 6.80k; Res_ohm: 6.8k; SizeX_mm: 1.6; SizeY_mm: 0.8; SizeZ_mm: 1; Value2: 0.1W; SizeArea_mm2: 1.28; AEC Qualified: N; VDC_V: 75V; AEC Category: Q200; SizeAreaWB_mm2: 4.68
R13-R17 R39 R40 R52 = CMP-0086358-1: RES, 0, 0%, 0.25 W, AEC-Q200 Grade 0, 0603; Manufacturer: Rohm; Power_W: 250mW; SizeZ_mm: 1; SizeArea_mm2: 1.28; Value2: 0.25W; SizeAreaWB_mm2: 4.68; Value_Code: 0000; Value: 0; AEC Qualified: Y; AEC Category: Q200; SizeX_mm: 1.6; SizeY_mm: 0.8
R18 = CMP-0025925-5: RES, 47 k, 5%, 0.1 W, 0603; Manufacturer: Yageo; Power_W: 100mW; TempCo: 100 ppm/C; Value_Code: 47k0; Value: 47k; EIA_Code: E24; SizeX_mm: 1.6; SizeY_mm: 0.8; SizeZ_mm: 1; Value2: 0.1W; SizeArea_mm2: 1.28; AEC Qualified: N; VDC_V: 75V; AEC Category: Q200; SizeAreaWB_mm2: 4.68
R21-R24 R29-R31 R67 R69-R72 = CMP-0025886-5: RES, 10 k, 5%, 0.1 W, 0603; Manufacturer: Yageo; Power_W: 100mW; TempCo: 100 ppm/C; Value_Code: 10k0; Value: 10k; EIA_Code: E24; SizeX_mm: 1.6; SizeY_mm: 0.8; SizeZ_mm: 1; Value2: 0.1W; SizeArea_mm2: 1.28; AEC Qualified: N; VDC_V: 75V; AEC Category: Q200; SizeAreaWB_mm2: 4.68
R25-R28 = CMP-2000-03817-1: Manufacturer: Vishay Dale
R53-R56 = CMP-0025862-4: RES, 8.2 k, 5%, 0.1 W, AEC-Q200 Grade 0, 0603; Manufacturer: Vishay-Dale; Power_W: 100mW; TempCo: 200 ppm/C; Value_Code: 8k20; Value: 8.2k; EIA_Code: E24; SizeX_mm: 1.6; SizeY_mm: 0.8; SizeZ_mm: 1; Value2: 0.1W; SizeArea_mm2: 1.28; AEC Qualified: Y; VDC_V: 75V; AEC Category: Q200; AEC Grade: 0
R57-R59 = CMP-0025757-4: RES, 22 k, 5%, 0.1 W, AEC-Q200 Grade 0, 0603; Manufacturer: Vishay-Dale; Power_W: 100mW; TempCo: 200 ppm/C; Value_Code: 22k0; Value: 22k; EIA_Code: E24; SizeX_mm: 1.6; SizeY_mm: 0.8; SizeZ_mm: 1; Value2: 0.1W; SizeArea_mm2: 1.28; AEC Qualified: Y; VDC_V: 75V; AEC Category: Q200; AEC Grade: 0
R60 = CMP-0025860-4: RES, 82 k, 5%, 0.1 W, AEC-Q200 Grade 0, 0603; Manufacturer: Vishay-Dale; Power_W: 100mW; TempCo: 200 ppm/C; Value_Code: 82k0; Value: 82k; EIA_Code: E24; SizeX_mm: 1.6; SizeY_mm: 0.8; SizeZ_mm: 1; Value2: 0.1W; SizeArea_mm2: 1.28; AEC Qualified: Y; VDC_V: 75V; AEC Category: Q200; AEC Grade: 0
R61-R63 = CMP-0022438-4: RES, 47.0 k, 1%, 0.1 W, AEC-Q200 Grade 0, 0603; Manufacturer: Vishay-Dale; Power_W: 100mW; TempCo: 100 ppm/C; Value_Code: 47k0; Value: 47.0k; Res_ohm: 47k; SizeX_mm: 1.6; SizeY_mm: 0.8; SizeZ_mm: 1; Value2: 0.1W; SizeArea_mm2: 1.28; AEC Qualified: Y; VDC_V: 75V; AEC Grade: 0; AEC Category: Q200
R64-R66 = CMP-0086261-1: RES, 100 k, 0.5%, 0.1 W, AEC-Q200 Grade 0, 0603; Manufacturer: Vishay-Dale; EIA_Code: E192; SizeZ_mm: 1; Power_W: 100mW; Value2: 0.1W; Value: 100k; SizeAreaWB_mm2: 4.68; AEC Qualified: Y; TempCo: 50 ppm/C; SizeArea_mm2: 1.28; AEC Category: Q200; SizeX_mm: 1.6; SizeY_mm: 0.8; AEC Grade: 0
R68 = CMP-0025886-3: RES, 10 k, 5%, 0.1 W, 0603; Manufacturer: Yageo America; Power_W: 100mW; TempCo: 100 ppm/C; Value_Code: 10k0; U/M: EA; Value: 10k; EIA_Code: E24; SizeX_mm: 1.6; SizeY_mm: 0.8; SizeZ_mm: 1; Value2: 0.1W; SizeArea_mm2: 1.28; VDC_V: 50V; AEC Category: Q200
S1 = CMP-0002134-3: Switch, Tactile, SPST-NO, 0.05A, 12V, SMT; Manufacturer: TE Connectivity; CurrentRating_mA: 50A; PositionCount: 1; SwitchFunction: Off-Mom
SH-J1-SH-J8 SH-J13-SH-J16 SH-J18-SH-J24 = CMP-0003761-2: Shunt, 2.54mm, Gold, Black; Manufacturer: Wurth Elektronik
TP1 TP2 TP5 = CMP-0055153-2: Test Point, Compact, SMT; Manufacturer: Keystone Electronics; Green_Lifecycle: Active; Green_REACh: Passed; CNHeader: FALSE; CT: TRUE
TP3 = CMP-0003719-1: Testpoint; Manufacturer: Texas Instruments; CompType: Pad
TP4 TP7 TP8 TP10-TP17 = CMP-0055147-2: Test Point, Multipurpose, Red, TH; Manufacturer: Keystone Electronics; CNHeader: FALSE; Green_Lifecycle: Active; Green_REACh: Passed; ContactFinish: Silver; CT: TRUE
TP6 = CMP-0055152-2: Test Point, Miniature, SMT; Manufacturer: Keystone Electronics; CNHeader: FALSE; Green_Lifecycle: Active; Green_REACh: Passed; CT: TRUE
TP9 = CMP-0055148-2: Test Point, Multipurpose, Black, TH; Manufacturer: Keystone Electronics; CNHeader: FALSE; Green_Lifecycle: Active; Green_REACh: Passed; ContactFinish: Silver; CT: TRUE
U1 = CMP-0121932-1: Automotive 65-V H-Bridge Driver with Integrated Current Sense and Diagnostics; Manufacturer: Texas Instruments; SizeZ_mm: 1mm; AEC Qualified: Yes; AEC Grade: Grade 1; Max Supply Voltage: 65V; Min Supply Voltage: 3V; Motor Type: Brushed; Nominal Supply Current: 3mA; Number Of Outputs: 2; Standoff Height: 0mm; Switching Frequency: 0-100kHz; TaMax_C: +125°C; TaMin_C: -40°C; TJmax_C: +150°C
U2 = CMP-0090815-1: LDO, Fixed Output, Dual, 3.3V, 10/12/15V, 50mA, Precision Enable, Power-Good, HVSSOP10; Manufacturer: Texas Instruments; Output Type: Fixed,Multi; Max Supply Voltage: 85V; TJmax_C: +125°C; Output Voltage: 3.3/10/12/15V; SizeZ_mm: 1.1mm; Dropout Voltage: 200/800mV; Min Supply Voltage: 4V; Standoff Height: 0.05mm; AEC Qualified: No; Number Of Outputs: 2; Accuracy Percentage: 1%; Nominal Supply Current: 100uA
U3 = CMP-0365-00685-2: 16 MHz Mixed Signal Microcontroller with 16 KB Flash, 512 B SRAM and 24 GPIOs, -40 to 85 degC, 28-pin SOP (PW), Green (RoHS & no Sb/Br); Manufacturer: Texas Instruments; Timers - 16-bit: 2; Watchdog: Yes; GPIO: 24; SRAM(B): 512; Frequency(MHz): 16; USCI_B (I2C & SPI): 1; SubFamily: Value Line; ADC Channels: 8; ADC: 10-bit SAR
U4 = CMP-0079180-1: Low Iq Always ON Smart Diode Controller, DBV0006A (SOT-23-6); Alternate PartNumber: LM74700QDBVRQ1; Alternate Manufacturer: Texas Instruments; SizeAreaWB_mm2: 14.82; SizeZ_mm: 1.45; SizeX_mm: 2.8; SizeY_mm: 2.9; SizeArea_mm2: 8.12; CompType: IC; AEC Qualified: Y; AEC Category: Q200

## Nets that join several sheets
3V3_MCU: ezFET (J7.10), MD093E1_DRV8263-Q1EVM_VQFN (14 pins)
GND: ezFET (46 pins), MD093E1_DRV8263-Q1EVM_VQFN (82 pins)
MCU_UARTRXD: ezFET (J7.8), MD093E1_DRV8263-Q1EVM_VQFN (U3.3)
MCU_UARTTXD: ezFET (J7.6), MD093E1_DRV8263-Q1EVM_VQFN (U3.4)
RST/SBWTDIO: ezFET (J7.4), MD093E1_DRV8263-Q1EVM_VQFN (C52.1 J1.1 R73.1 U3.24)
TST/SBWTCK: ezFET (J7.2), MD093E1_DRV8263-Q1EVM_VQFN (U3.25)

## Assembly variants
001: not fitted C3 C38 C39 C53 J10 J11 J12 J13 R13 R14 R15 R16 R17 R21 R22 R23 R24 R30 R31 R39 R40 R42 R52 R53 R54 R55 R56 R57 R58 R59 R60 R61 R62 R63 R64 R65 R66 R68 R70 R71 R72 SH-J2 SH-J3 SH-J4 SH-J5
002: not fitted C3 C38 C39 C53 R22 R23 R25 R26 R27 R28 R29 R30 R31 R42 R60 R68 R70 R71 R72 SH-J15 SH-J18 SH-J22 SH-J23; alternate parts U1 -> CMP-0121931-1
